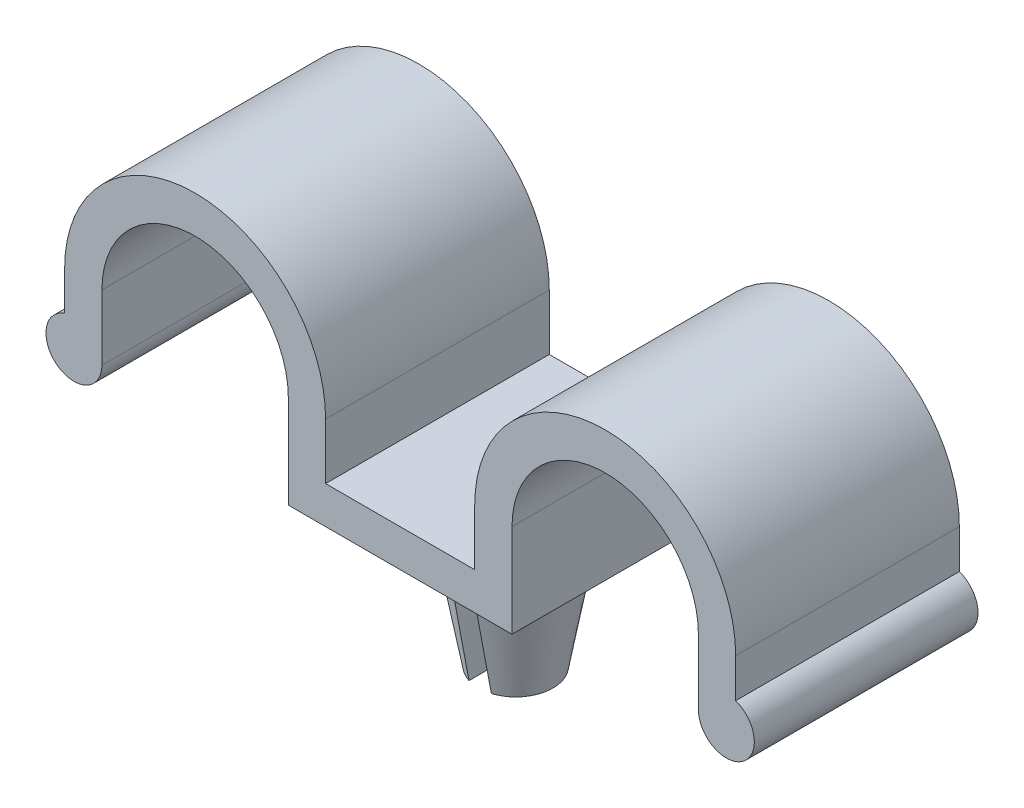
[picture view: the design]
ISO-10303-21;
HEADER;
FILE_DESCRIPTION(('STEP AP214'),'2;1');
FILE_NAME('part.step','',(''),(''),'','','');
FILE_SCHEMA(('AUTOMOTIVE_DESIGN { 1 0 10303 214 1 1 1 1 }'));
ENDSEC;
DATA;
#1=APPLICATION_CONTEXT('core data for automotive mechanical design processes');
#2=APPLICATION_PROTOCOL_DEFINITION('international standard','automotive_design',2000,#1);
#3=PRODUCT_CONTEXT('',#1,'mechanical');
#4=PRODUCT('Part','Part','',(#3));
#5=PRODUCT_RELATED_PRODUCT_CATEGORY('part','',(#4));
#6=PRODUCT_DEFINITION_FORMATION('','',#4);
#7=PRODUCT_DEFINITION_CONTEXT('part definition',#1,'design');
#8=PRODUCT_DEFINITION('design','',#6,#7);
#9=PRODUCT_DEFINITION_SHAPE('','',#8);
#10=(LENGTH_UNIT() NAMED_UNIT(*) SI_UNIT(.MILLI.,.METRE.));
#11=(NAMED_UNIT(*) PLANE_ANGLE_UNIT() SI_UNIT($,.RADIAN.));
#12=(NAMED_UNIT(*) SI_UNIT($,.STERADIAN.) SOLID_ANGLE_UNIT());
#13=UNCERTAINTY_MEASURE_WITH_UNIT(LENGTH_MEASURE(1.E-05),#10,'distance_accuracy_value','');
#14=(GEOMETRIC_REPRESENTATION_CONTEXT(3) GLOBAL_UNCERTAINTY_ASSIGNED_CONTEXT((#13)) GLOBAL_UNIT_ASSIGNED_CONTEXT((#10,
#11,#12)) REPRESENTATION_CONTEXT('',''));
#15=CARTESIAN_POINT('',(0.,0.,0.));
#16=DIRECTION('',(0.,0.,1.));
#17=DIRECTION('',(1.,0.,0.));
#18=AXIS2_PLACEMENT_3D('',#15,#16,#17);
#19=CARTESIAN_POINT('',(-6.858,-7.874,0.));
#20=DIRECTION('',(0.,-1.,0.));
#21=DIRECTION('',(0.,0.,-1.));
#22=AXIS2_PLACEMENT_3D('',#19,#20,#21);
#23=PLANE('',#22);
#24=DIRECTION('',(0.,0.,1.));
#25=VECTOR('',#24,1.);
#26=CARTESIAN_POINT('',(-7.239,-7.874,-3.81));
#27=LINE('',#26,#25);
#28=CARTESIAN_POINT('',(-7.239,-7.874,-1.21150278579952));
#29=VERTEX_POINT('',#28);
#30=CARTESIAN_POINT('',(-7.239,-7.874,1.21150278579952));
#31=VERTEX_POINT('',#30);
#32=EDGE_CURVE('E524',#29,#31,#27,.T.);
#33=ORIENTED_EDGE('',*,*,#32,.T.);
#34=CARTESIAN_POINT('',(-6.858,-7.874,0.));
#35=DIRECTION('',(0.,-1.,0.));
#36=DIRECTION('',(0.,0.,-1.));
#37=AXIS2_PLACEMENT_3D('',#34,#35,#36);
#38=CIRCLE('',#37,1.27);
#39=EDGE_CURVE('E413',#31,#29,#38,.T.);
#40=ORIENTED_EDGE('',*,*,#39,.T.);
#41=EDGE_LOOP('',(#33,#40));
#42=FACE_BOUND('',#41,.T.);
#43=ADVANCED_FACE('F34',(#42),#23,.T.);
#44=CARTESIAN_POINT('',(-6.858,-7.874,0.));
#45=DIRECTION('',(0.,1.,0.));
#46=DIRECTION('',(0.,0.,1.));
#47=AXIS2_PLACEMENT_3D('',#44,#45,#46);
#48=CONICAL_SURFACE('',#47,1.27,0.179853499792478);
#49=CARTESIAN_POINT('',(-7.239,-9.73878944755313,-0.849412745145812));
#50=CARTESIAN_POINT('',(-7.239,-9.48062278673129,-0.900807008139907));
#51=CARTESIAN_POINT('',(-7.239,-9.22232851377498,-0.951552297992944));
#52=CARTESIAN_POINT('',(-7.239,-8.7055574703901,-1.05209980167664));
#53=CARTESIAN_POINT('',(-7.239,-8.4470807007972,-1.10190201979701));
#54=CARTESIAN_POINT('',(-7.239,-7.96393825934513,-1.1944225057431));
#55=CARTESIAN_POINT('',(-7.239,-7.73928633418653,-1.2372128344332));
#56=CARTESIAN_POINT('',(-7.239,-7.14364629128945,-1.35021271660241));
#57=CARTESIAN_POINT('',(-7.239,-6.77260404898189,-1.42013701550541));
#58=CARTESIAN_POINT('',(-7.239,-6.03041303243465,-1.55941958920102));
#59=CARTESIAN_POINT('',(-7.239,-5.65926425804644,-1.62877786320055));
#60=CARTESIAN_POINT('',(-7.239,-4.58924213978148,-1.82817101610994));
#61=CARTESIAN_POINT('',(-7.239,-3.89027873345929,-1.95772240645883));
#62=CARTESIAN_POINT('',(-7.239,-2.49221927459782,-2.21610859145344));
#63=CARTESIAN_POINT('',(-7.23900000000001,-1.79312322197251,-2.34494338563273));
#64=CARTESIAN_POINT('',(-7.23900000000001,-0.394858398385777,-2.60217341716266));
#65=CARTESIAN_POINT('',(-7.23900000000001,0.304310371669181,-2.73056865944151));
#66=CARTESIAN_POINT('',(-7.23900000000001,1.7027014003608,-2.98706215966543));
#67=CARTESIAN_POINT('',(-7.23900000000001,2.40192365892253,-3.11516041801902));
#68=CARTESIAN_POINT('',(-7.23900000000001,3.10116007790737,-3.24318091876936));
#69=B_SPLINE_CURVE_WITH_KNOTS('',3,(#49,#50,#51,#52,#53,#54,#55,#56,#57,#58,#59,#60,#61,#62,#63,
#64,#65,#66,#67,#68),.UNSPECIFIED.,.F.,.F.,(4,2,2,2,2,2,2,2,2,4),(0.,0.789694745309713,
1.57938589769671,2.26545823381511,3.39817786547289,4.53089908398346,6.66350237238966,
8.7961070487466,10.9286877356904,13.0612654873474),.UNSPECIFIED.);
#70=CARTESIAN_POINT('',(-7.239,-5.08,-1.73669888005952));
#71=VERTEX_POINT('',#70);
#72=EDGE_CURVE('E396',#29,#71,#69,.T.);
#73=ORIENTED_EDGE('',*,*,#72,.F.);
#74=ORIENTED_EDGE('',*,*,#39,.F.);
#75=CARTESIAN_POINT('',(-7.239,-9.73878944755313,0.849412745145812));
#76=CARTESIAN_POINT('',(-7.239,-9.48062278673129,0.900807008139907));
#77=CARTESIAN_POINT('',(-7.239,-9.22232851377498,0.951552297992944));
#78=CARTESIAN_POINT('',(-7.239,-8.7055574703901,1.05209980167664));
#79=CARTESIAN_POINT('',(-7.239,-8.4470807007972,1.10190201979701));
#80=CARTESIAN_POINT('',(-7.239,-7.96393825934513,1.1944225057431));
#81=CARTESIAN_POINT('',(-7.239,-7.73928633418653,1.2372128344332));
#82=CARTESIAN_POINT('',(-7.239,-7.14364629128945,1.35021271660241));
#83=CARTESIAN_POINT('',(-7.239,-6.77260404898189,1.42013701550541));
#84=CARTESIAN_POINT('',(-7.239,-6.03041303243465,1.55941958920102));
#85=CARTESIAN_POINT('',(-7.239,-5.65926425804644,1.62877786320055));
#86=CARTESIAN_POINT('',(-7.239,-4.58924213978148,1.82817101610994));
#87=CARTESIAN_POINT('',(-7.239,-3.89027873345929,1.95772240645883));
#88=CARTESIAN_POINT('',(-7.239,-2.49221927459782,2.21610859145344));
#89=CARTESIAN_POINT('',(-7.23900000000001,-1.79312322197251,2.34494338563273));
#90=CARTESIAN_POINT('',(-7.23900000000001,-0.394858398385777,2.60217341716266));
#91=CARTESIAN_POINT('',(-7.23900000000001,0.304310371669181,2.73056865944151));
#92=CARTESIAN_POINT('',(-7.23900000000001,1.7027014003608,2.98706215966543));
#93=CARTESIAN_POINT('',(-7.23900000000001,2.40192365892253,3.11516041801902));
#94=CARTESIAN_POINT('',(-7.23900000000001,3.10116007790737,3.24318091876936));
#95=B_SPLINE_CURVE_WITH_KNOTS('',3,(#75,#76,#77,#78,#79,#80,#81,#82,#83,#84,#85,#86,#87,#88,#89,
#90,#91,#92,#93,#94),.UNSPECIFIED.,.F.,.F.,(4,2,2,2,2,2,2,2,2,4),(0.,0.789694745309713,
1.57938589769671,2.26545823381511,3.39817786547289,4.53089908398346,6.66350237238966,
8.7961070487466,10.9286877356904,13.0612654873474),.UNSPECIFIED.);
#96=CARTESIAN_POINT('',(-7.239,-5.08,1.73669888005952));
#97=VERTEX_POINT('',#96);
#98=EDGE_CURVE('E383',#97,#31,#95,.F.);
#99=ORIENTED_EDGE('',*,*,#98,.F.);
#100=CARTESIAN_POINT('',(-6.858,-5.08,0.));
#101=DIRECTION('',(0.,-1.,0.));
#102=DIRECTION('',(0.,0.,-1.));
#103=AXIS2_PLACEMENT_3D('',#100,#101,#102);
#104=CIRCLE('',#103,1.778);
#105=EDGE_CURVE('E409',#97,#71,#104,.T.);
#106=ORIENTED_EDGE('',*,*,#105,.T.);
#107=EDGE_LOOP('',(#73,#74,#99,#106));
#108=FACE_BOUND('',#107,.T.);
#109=ADVANCED_FACE('F371',(#108),#48,.T.);
#110=CARTESIAN_POINT('',(-6.858,-3.175,0.));
#111=DIRECTION('',(0.,-1.,0.));
#112=DIRECTION('',(0.,0.,-1.));
#113=AXIS2_PLACEMENT_3D('',#110,#111,#112);
#114=CYLINDRICAL_SURFACE('',#113,1.778);
#115=DIRECTION('',(0.,-1.,0.));
#116=VECTOR('',#115,1.);
#117=CARTESIAN_POINT('',(-7.239,-3.175,-1.73669888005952));
#118=LINE('',#117,#116);
#119=CARTESIAN_POINT('',(-7.239,-4.826,-1.73669888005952));
#120=VERTEX_POINT('',#119);
#121=EDGE_CURVE('E392',#71,#120,#118,.F.);
#122=ORIENTED_EDGE('',*,*,#121,.F.);
#123=ORIENTED_EDGE('',*,*,#105,.F.);
#124=DIRECTION('',(0.,-1.,0.));
#125=VECTOR('',#124,1.);
#126=CARTESIAN_POINT('',(-7.239,-3.175,1.73669888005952));
#127=LINE('',#126,#125);
#128=CARTESIAN_POINT('',(-7.239,-4.826,1.73669888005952));
#129=VERTEX_POINT('',#128);
#130=EDGE_CURVE('E391',#129,#97,#127,.T.);
#131=ORIENTED_EDGE('',*,*,#130,.F.);
#132=CARTESIAN_POINT('',(-6.858,-4.826,0.));
#133=DIRECTION('',(0.,-1.,0.));
#134=DIRECTION('',(0.,0.,-1.));
#135=AXIS2_PLACEMENT_3D('',#132,#133,#134);
#136=CIRCLE('',#135,1.778);
#137=EDGE_CURVE('E407',#129,#120,#136,.T.);
#138=ORIENTED_EDGE('',*,*,#137,.T.);
#139=EDGE_LOOP('',(#122,#123,#131,#138));
#140=FACE_BOUND('',#139,.T.);
#141=ADVANCED_FACE('F511',(#140),#114,.T.);
#142=CARTESIAN_POINT('',(-5.08,-4.826,0.));
#143=DIRECTION('',(0.,1.,0.));
#144=DIRECTION('',(0.,0.,1.));
#145=AXIS2_PLACEMENT_3D('',#142,#143,#144);
#146=PLANE('',#145);
#147=DIRECTION('',(0.,0.,1.));
#148=VECTOR('',#147,1.);
#149=CARTESIAN_POINT('',(-7.239,-4.826,0.));
#150=LINE('',#149,#148);
#151=CARTESIAN_POINT('',(-7.239,-4.826,-1.47560665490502));
#152=VERTEX_POINT('',#151);
#153=EDGE_CURVE('E310',#120,#152,#150,.T.);
#154=ORIENTED_EDGE('',*,*,#153,.F.);
#155=ORIENTED_EDGE('',*,*,#137,.F.);
#156=CARTESIAN_POINT('',(-7.239,-4.826,1.47560665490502));
#157=VERTEX_POINT('',#156);
#158=EDGE_CURVE('E530',#157,#129,#150,.T.);
#159=ORIENTED_EDGE('',*,*,#158,.F.);
#160=CARTESIAN_POINT('',(-6.858,-4.826,0.));
#161=DIRECTION('',(0.,-1.,0.));
#162=DIRECTION('',(0.,0.,-1.));
#163=AXIS2_PLACEMENT_3D('',#160,#161,#162);
#164=CIRCLE('',#163,1.524);
#165=EDGE_CURVE('E405',#157,#152,#164,.T.);
#166=ORIENTED_EDGE('',*,*,#165,.T.);
#167=EDGE_LOOP('',(#154,#155,#159,#166));
#168=FACE_BOUND('',#167,.T.);
#169=ADVANCED_FACE('F546',(#168),#146,.T.);
#170=CARTESIAN_POINT('',(-3.175,-3.175,3.81));
#171=DIRECTION('',(0.,1.,0.));
#172=DIRECTION('',(-1.,0.,0.));
#173=AXIS2_PLACEMENT_3D('',#170,#171,#172);
#174=PLANE('',#173);
#175=CARTESIAN_POINT('',(-6.858,-3.175,0.));
#176=DIRECTION('',(0.,-1.,0.));
#177=DIRECTION('',(0.,0.,-1.));
#178=AXIS2_PLACEMENT_3D('',#175,#176,#177);
#179=CIRCLE('',#178,1.524);
#180=CARTESIAN_POINT('',(-6.858,-3.175,-1.524));
#181=VERTEX_POINT('',#180);
#182=EDGE_CURVE('E402',#181,#181,#179,.T.);
#183=ORIENTED_EDGE('',*,*,#182,.F.);
#184=EDGE_LOOP('',(#183));
#185=FACE_BOUND('',#184,.T.);
#186=DIRECTION('',(1.,0.,0.));
#187=VECTOR('',#186,1.);
#188=CARTESIAN_POINT('',(-3.175,-3.175,-3.81));
#189=LINE('',#188,#187);
#190=CARTESIAN_POINT('',(-10.795,-3.175,-3.81));
#191=VERTEX_POINT('',#190);
#192=CARTESIAN_POINT('',(-3.175,-3.175,-3.81));
#193=VERTEX_POINT('',#192);
#194=EDGE_CURVE('E191',#191,#193,#189,.T.);
#195=ORIENTED_EDGE('',*,*,#194,.T.);
#196=DIRECTION('',(0.,0.,-1.));
#197=VECTOR('',#196,1.);
#198=CARTESIAN_POINT('',(-3.175,-3.175,3.81));
#199=LINE('',#198,#197);
#200=CARTESIAN_POINT('',(-3.175,-3.175,3.81));
#201=VERTEX_POINT('',#200);
#202=EDGE_CURVE('E260',#201,#193,#199,.T.);
#203=ORIENTED_EDGE('',*,*,#202,.F.);
#204=DIRECTION('',(1.,0.,0.));
#205=VECTOR('',#204,1.);
#206=CARTESIAN_POINT('',(-3.175,-3.175,3.81));
#207=LINE('',#206,#205);
#208=CARTESIAN_POINT('',(-10.795,-3.175,3.81));
#209=VERTEX_POINT('',#208);
#210=EDGE_CURVE('E223',#209,#201,#207,.T.);
#211=ORIENTED_EDGE('',*,*,#210,.F.);
#212=DIRECTION('',(0.,0.,-1.));
#213=VECTOR('',#212,1.);
#214=CARTESIAN_POINT('',(-10.795,-3.175,3.81));
#215=LINE('',#214,#213);
#216=EDGE_CURVE('E187',#209,#191,#215,.T.);
#217=ORIENTED_EDGE('',*,*,#216,.T.);
#218=EDGE_LOOP('',(#195,#203,#211,#217));
#219=FACE_BOUND('',#218,.T.);
#220=ADVANCED_FACE('F36',(#185,#219),#174,.F.);
#221=CARTESIAN_POINT('',(-3.175,0.,3.81));
#222=DIRECTION('',(-1.,0.,0.));
#223=DIRECTION('',(0.,0.,1.));
#224=AXIS2_PLACEMENT_3D('',#221,#222,#223);
#225=PLANE('',#224);
#226=DIRECTION('',(0.,1.,0.));
#227=VECTOR('',#226,1.);
#228=CARTESIAN_POINT('',(-3.175,0.,-3.81));
#229=LINE('',#228,#227);
#230=CARTESIAN_POINT('',(-3.175,0.,-3.81));
#231=VERTEX_POINT('',#230);
#232=EDGE_CURVE('E194',#193,#231,#229,.T.);
#233=ORIENTED_EDGE('',*,*,#232,.T.);
#234=DIRECTION('',(0.,0.,-1.));
#235=VECTOR('',#234,1.);
#236=CARTESIAN_POINT('',(-3.175,0.,3.81));
#237=LINE('',#236,#235);
#238=CARTESIAN_POINT('',(-3.175,0.,3.81));
#239=VERTEX_POINT('',#238);
#240=EDGE_CURVE('E257',#239,#231,#237,.T.);
#241=ORIENTED_EDGE('',*,*,#240,.F.);
#242=DIRECTION('',(0.,1.,0.));
#243=VECTOR('',#242,1.);
#244=CARTESIAN_POINT('',(-3.175,0.,3.81));
#245=LINE('',#244,#243);
#246=EDGE_CURVE('E124',#201,#239,#245,.T.);
#247=ORIENTED_EDGE('',*,*,#246,.F.);
#248=ORIENTED_EDGE('',*,*,#202,.T.);
#249=EDGE_LOOP('',(#233,#241,#247,#248));
#250=FACE_BOUND('',#249,.T.);
#251=ADVANCED_FACE('F456',(#250),#225,.F.);
#252=CARTESIAN_POINT('',(0.,0.,3.81));
#253=DIRECTION('',(0.,0.,-1.));
#254=DIRECTION('',(-1.,0.,0.));
#255=AXIS2_PLACEMENT_3D('',#252,#253,#254);
#256=CYLINDRICAL_SURFACE('',#255,3.175);
#257=CARTESIAN_POINT('',(0.,0.,-3.81));
#258=DIRECTION('',(0.,0.,-1.));
#259=DIRECTION('',(1.,0.,0.));
#260=AXIS2_PLACEMENT_3D('',#257,#258,#259);
#261=CIRCLE('',#260,3.175);
#262=CARTESIAN_POINT('',(3.175,0.,-3.81));
#263=VERTEX_POINT('',#262);
#264=EDGE_CURVE('E197',#231,#263,#261,.T.);
#265=ORIENTED_EDGE('',*,*,#264,.T.);
#266=DIRECTION('',(0.,0.,-1.));
#267=VECTOR('',#266,1.);
#268=CARTESIAN_POINT('',(3.175,0.,3.81));
#269=LINE('',#268,#267);
#270=CARTESIAN_POINT('',(3.175,0.,3.81));
#271=VERTEX_POINT('',#270);
#272=EDGE_CURVE('E254',#271,#263,#269,.T.);
#273=ORIENTED_EDGE('',*,*,#272,.F.);
#274=CARTESIAN_POINT('',(0.,0.,3.81));
#275=DIRECTION('',(0.,0.,-1.));
#276=DIRECTION('',(1.,0.,0.));
#277=AXIS2_PLACEMENT_3D('',#274,#275,#276);
#278=CIRCLE('',#277,3.175);
#279=EDGE_CURVE('E418',#239,#271,#278,.T.);
#280=ORIENTED_EDGE('',*,*,#279,.F.);
#281=ORIENTED_EDGE('',*,*,#240,.T.);
#282=EDGE_LOOP('',(#265,#273,#280,#281));
#283=FACE_BOUND('',#282,.T.);
#284=ADVANCED_FACE('F459',(#283),#256,.F.);
#285=CARTESIAN_POINT('',(3.175,0.,3.81));
#286=DIRECTION('',(1.,0.,0.));
#287=DIRECTION('',(0.,1.,0.));
#288=AXIS2_PLACEMENT_3D('',#285,#286,#287);
#289=PLANE('',#288);
#290=DIRECTION('',(0.,-1.,0.));
#291=VECTOR('',#290,1.);
#292=CARTESIAN_POINT('',(3.175,0.,-3.81));
#293=LINE('',#292,#291);
#294=CARTESIAN_POINT('',(3.175,-2.2225,-3.81));
#295=VERTEX_POINT('',#294);
#296=EDGE_CURVE('E199',#263,#295,#293,.T.);
#297=ORIENTED_EDGE('',*,*,#296,.T.);
#298=DIRECTION('',(0.,0.,-1.));
#299=VECTOR('',#298,1.);
#300=CARTESIAN_POINT('',(3.175,-2.2225,3.81));
#301=LINE('',#300,#299);
#302=CARTESIAN_POINT('',(3.175,-2.2225,3.81));
#303=VERTEX_POINT('',#302);
#304=EDGE_CURVE('E251',#303,#295,#301,.T.);
#305=ORIENTED_EDGE('',*,*,#304,.F.);
#306=DIRECTION('',(0.,-1.,0.));
#307=VECTOR('',#306,1.);
#308=CARTESIAN_POINT('',(3.175,0.,3.81));
#309=LINE('',#308,#307);
#310=EDGE_CURVE('E420',#271,#303,#309,.T.);
#311=ORIENTED_EDGE('',*,*,#310,.F.);
#312=ORIENTED_EDGE('',*,*,#272,.T.);
#313=EDGE_LOOP('',(#297,#305,#311,#312));
#314=FACE_BOUND('',#313,.T.);
#315=ADVANCED_FACE('F464',(#314),#289,.F.);
#316=CARTESIAN_POINT('',(4.1275,-2.2225,3.81));
#317=DIRECTION('',(0.,0.,-1.));
#318=DIRECTION('',(-1.,0.,0.));
#319=AXIS2_PLACEMENT_3D('',#316,#317,#318);
#320=CYLINDRICAL_SURFACE('',#319,0.9525);
#321=CARTESIAN_POINT('',(4.1275,-2.2225,-3.81));
#322=DIRECTION('',(0.,0.,1.));
#323=DIRECTION('',(1.,0.,0.));
#324=AXIS2_PLACEMENT_3D('',#321,#322,#323);
#325=CIRCLE('',#324,0.9525);
#326=CARTESIAN_POINT('',(4.445,-1.32447438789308,-3.81));
#327=VERTEX_POINT('',#326);
#328=EDGE_CURVE('E201',#295,#327,#325,.T.);
#329=ORIENTED_EDGE('',*,*,#328,.T.);
#330=DIRECTION('',(0.,0.,-1.));
#331=VECTOR('',#330,1.);
#332=CARTESIAN_POINT('',(4.445,-1.32447438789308,3.81));
#333=LINE('',#332,#331);
#334=CARTESIAN_POINT('',(4.445,-1.32447438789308,3.81));
#335=VERTEX_POINT('',#334);
#336=EDGE_CURVE('E248',#335,#327,#333,.T.);
#337=ORIENTED_EDGE('',*,*,#336,.F.);
#338=CARTESIAN_POINT('',(4.1275,-2.2225,3.81));
#339=DIRECTION('',(0.,0.,1.));
#340=DIRECTION('',(1.,0.,0.));
#341=AXIS2_PLACEMENT_3D('',#338,#339,#340);
#342=CIRCLE('',#341,0.9525);
#343=EDGE_CURVE('E422',#303,#335,#342,.T.);
#344=ORIENTED_EDGE('',*,*,#343,.F.);
#345=ORIENTED_EDGE('',*,*,#304,.T.);
#346=EDGE_LOOP('',(#329,#337,#344,#345));
#347=FACE_BOUND('',#346,.T.);
#348=ADVANCED_FACE('F470',(#347),#320,.T.);
#349=CARTESIAN_POINT('',(4.445,0.,3.81));
#350=DIRECTION('',(-1.,0.,0.));
#351=DIRECTION('',(0.,0.,1.));
#352=AXIS2_PLACEMENT_3D('',#349,#350,#351);
#353=PLANE('',#352);
#354=DIRECTION('',(0.,1.,0.));
#355=VECTOR('',#354,1.);
#356=CARTESIAN_POINT('',(4.445,0.,-3.81));
#357=LINE('',#356,#355);
#358=CARTESIAN_POINT('',(4.445,0.,-3.81));
#359=VERTEX_POINT('',#358);
#360=EDGE_CURVE('E203',#327,#359,#357,.T.);
#361=ORIENTED_EDGE('',*,*,#360,.T.);
#362=DIRECTION('',(0.,0.,-1.));
#363=VECTOR('',#362,1.);
#364=CARTESIAN_POINT('',(4.445,0.,3.81));
#365=LINE('',#364,#363);
#366=CARTESIAN_POINT('',(4.445,0.,3.81));
#367=VERTEX_POINT('',#366);
#368=EDGE_CURVE('E245',#367,#359,#365,.T.);
#369=ORIENTED_EDGE('',*,*,#368,.F.);
#370=DIRECTION('',(0.,1.,0.));
#371=VECTOR('',#370,1.);
#372=CARTESIAN_POINT('',(4.445,0.,3.81));
#373=LINE('',#372,#371);
#374=EDGE_CURVE('E424',#335,#367,#373,.T.);
#375=ORIENTED_EDGE('',*,*,#374,.F.);
#376=ORIENTED_EDGE('',*,*,#336,.T.);
#377=EDGE_LOOP('',(#361,#369,#375,#376));
#378=FACE_BOUND('',#377,.T.);
#379=ADVANCED_FACE('F474',(#378),#353,.F.);
#380=CARTESIAN_POINT('',(0.,0.,3.81));
#381=DIRECTION('',(0.,0.,-1.));
#382=DIRECTION('',(-1.,0.,0.));
#383=AXIS2_PLACEMENT_3D('',#380,#381,#382);
#384=CYLINDRICAL_SURFACE('',#383,4.445);
#385=CARTESIAN_POINT('',(0.,0.,-3.81));
#386=DIRECTION('',(0.,0.,1.));
#387=DIRECTION('',(1.,0.,0.));
#388=AXIS2_PLACEMENT_3D('',#385,#386,#387);
#389=CIRCLE('',#388,4.445);
#390=CARTESIAN_POINT('',(-4.445,0.,-3.81));
#391=VERTEX_POINT('',#390);
#392=EDGE_CURVE('E205',#359,#391,#389,.T.);
#393=ORIENTED_EDGE('',*,*,#392,.T.);
#394=DIRECTION('',(0.,0.,-1.));
#395=VECTOR('',#394,1.);
#396=CARTESIAN_POINT('',(-4.445,0.,3.81));
#397=LINE('',#396,#395);
#398=CARTESIAN_POINT('',(-4.445,0.,3.81));
#399=VERTEX_POINT('',#398);
#400=EDGE_CURVE('E242',#399,#391,#397,.T.);
#401=ORIENTED_EDGE('',*,*,#400,.F.);
#402=CARTESIAN_POINT('',(0.,0.,3.81));
#403=DIRECTION('',(0.,0.,1.));
#404=DIRECTION('',(1.,0.,0.));
#405=AXIS2_PLACEMENT_3D('',#402,#403,#404);
#406=CIRCLE('',#405,4.445);
#407=EDGE_CURVE('E426',#367,#399,#406,.T.);
#408=ORIENTED_EDGE('',*,*,#407,.F.);
#409=ORIENTED_EDGE('',*,*,#368,.T.);
#410=EDGE_LOOP('',(#393,#401,#408,#409));
#411=FACE_BOUND('',#410,.T.);
#412=ADVANCED_FACE('F479',(#411),#384,.T.);
#413=CARTESIAN_POINT('',(-4.445,0.,3.81));
#414=DIRECTION('',(1.,0.,0.));
#415=DIRECTION('',(0.,0.,-1.));
#416=AXIS2_PLACEMENT_3D('',#413,#414,#415);
#417=PLANE('',#416);
#418=DIRECTION('',(0.,-1.,0.));
#419=VECTOR('',#418,1.);
#420=CARTESIAN_POINT('',(-4.445,0.,-3.81));
#421=LINE('',#420,#419);
#422=CARTESIAN_POINT('',(-4.445,-1.905,-3.81));
#423=VERTEX_POINT('',#422);
#424=EDGE_CURVE('E207',#391,#423,#421,.T.);
#425=ORIENTED_EDGE('',*,*,#424,.T.);
#426=DIRECTION('',(0.,0.,-1.));
#427=VECTOR('',#426,1.);
#428=CARTESIAN_POINT('',(-4.445,-1.905,3.81));
#429=LINE('',#428,#427);
#430=CARTESIAN_POINT('',(-4.445,-1.905,3.81));
#431=VERTEX_POINT('',#430);
#432=EDGE_CURVE('E239',#431,#423,#429,.T.);
#433=ORIENTED_EDGE('',*,*,#432,.F.);
#434=DIRECTION('',(0.,-1.,0.));
#435=VECTOR('',#434,1.);
#436=CARTESIAN_POINT('',(-4.445,0.,3.81));
#437=LINE('',#436,#435);
#438=EDGE_CURVE('E428',#399,#431,#437,.T.);
#439=ORIENTED_EDGE('',*,*,#438,.F.);
#440=ORIENTED_EDGE('',*,*,#400,.T.);
#441=EDGE_LOOP('',(#425,#433,#439,#440));
#442=FACE_BOUND('',#441,.T.);
#443=ADVANCED_FACE('F485',(#442),#417,.F.);
#444=CARTESIAN_POINT('',(-9.525,-1.905,3.81));
#445=DIRECTION('',(0.,-1.,0.));
#446=DIRECTION('',(1.,0.,0.));
#447=AXIS2_PLACEMENT_3D('',#444,#445,#446);
#448=PLANE('',#447);
#449=DIRECTION('',(-1.,0.,0.));
#450=VECTOR('',#449,1.);
#451=CARTESIAN_POINT('',(-9.525,-1.905,-3.81));
#452=LINE('',#451,#450);
#453=CARTESIAN_POINT('',(-9.525,-1.905,-3.81));
#454=VERTEX_POINT('',#453);
#455=EDGE_CURVE('E209',#423,#454,#452,.T.);
#456=ORIENTED_EDGE('',*,*,#455,.T.);
#457=DIRECTION('',(0.,0.,-1.));
#458=VECTOR('',#457,1.);
#459=CARTESIAN_POINT('',(-9.525,-1.905,3.81));
#460=LINE('',#459,#458);
#461=CARTESIAN_POINT('',(-9.525,-1.905,3.81));
#462=VERTEX_POINT('',#461);
#463=EDGE_CURVE('E236',#462,#454,#460,.T.);
#464=ORIENTED_EDGE('',*,*,#463,.F.);
#465=DIRECTION('',(-1.,0.,0.));
#466=VECTOR('',#465,1.);
#467=CARTESIAN_POINT('',(-9.525,-1.905,3.81));
#468=LINE('',#467,#466);
#469=EDGE_CURVE('E430',#431,#462,#468,.T.);
#470=ORIENTED_EDGE('',*,*,#469,.F.);
#471=ORIENTED_EDGE('',*,*,#432,.T.);
#472=EDGE_LOOP('',(#456,#464,#470,#471));
#473=FACE_BOUND('',#472,.T.);
#474=ADVANCED_FACE('F489',(#473),#448,.F.);
#475=CARTESIAN_POINT('',(-9.525,0.,3.81));
#476=DIRECTION('',(-1.,0.,0.));
#477=DIRECTION('',(0.,0.,1.));
#478=AXIS2_PLACEMENT_3D('',#475,#476,#477);
#479=PLANE('',#478);
#480=DIRECTION('',(0.,1.,0.));
#481=VECTOR('',#480,1.);
#482=CARTESIAN_POINT('',(-9.525,0.,-3.81));
#483=LINE('',#482,#481);
#484=CARTESIAN_POINT('',(-9.525,0.,-3.81));
#485=VERTEX_POINT('',#484);
#486=EDGE_CURVE('E211',#454,#485,#483,.T.);
#487=ORIENTED_EDGE('',*,*,#486,.T.);
#488=DIRECTION('',(0.,0.,-1.));
#489=VECTOR('',#488,1.);
#490=CARTESIAN_POINT('',(-9.525,0.,3.81));
#491=LINE('',#490,#489);
#492=CARTESIAN_POINT('',(-9.525,0.,3.81));
#493=VERTEX_POINT('',#492);
#494=EDGE_CURVE('E233',#493,#485,#491,.T.);
#495=ORIENTED_EDGE('',*,*,#494,.F.);
#496=DIRECTION('',(0.,1.,0.));
#497=VECTOR('',#496,1.);
#498=CARTESIAN_POINT('',(-9.525,0.,3.81));
#499=LINE('',#498,#497);
#500=EDGE_CURVE('E432',#462,#493,#499,.T.);
#501=ORIENTED_EDGE('',*,*,#500,.F.);
#502=ORIENTED_EDGE('',*,*,#463,.T.);
#503=EDGE_LOOP('',(#487,#495,#501,#502));
#504=FACE_BOUND('',#503,.T.);
#505=ADVANCED_FACE('F494',(#504),#479,.F.);
#506=CARTESIAN_POINT('',(-13.97,0.,3.81));
#507=DIRECTION('',(0.,0.,-1.));
#508=DIRECTION('',(-1.,0.,0.));
#509=AXIS2_PLACEMENT_3D('',#506,#507,#508);
#510=CYLINDRICAL_SURFACE('',#509,4.445);
#511=CARTESIAN_POINT('',(-13.97,0.,-3.81));
#512=DIRECTION('',(0.,0.,1.));
#513=DIRECTION('',(-1.,0.,0.));
#514=AXIS2_PLACEMENT_3D('',#511,#512,#513);
#515=CIRCLE('',#514,4.445);
#516=CARTESIAN_POINT('',(-18.415,0.,-3.81));
#517=VERTEX_POINT('',#516);
#518=EDGE_CURVE('E213',#485,#517,#515,.T.);
#519=ORIENTED_EDGE('',*,*,#518,.T.);
#520=DIRECTION('',(0.,0.,-1.));
#521=VECTOR('',#520,1.);
#522=CARTESIAN_POINT('',(-18.415,0.,3.81));
#523=LINE('',#522,#521);
#524=CARTESIAN_POINT('',(-18.415,0.,3.81));
#525=VERTEX_POINT('',#524);
#526=EDGE_CURVE('E230',#525,#517,#523,.T.);
#527=ORIENTED_EDGE('',*,*,#526,.F.);
#528=CARTESIAN_POINT('',(-13.97,0.,3.81));
#529=DIRECTION('',(0.,0.,1.));
#530=DIRECTION('',(-1.,0.,0.));
#531=AXIS2_PLACEMENT_3D('',#528,#529,#530);
#532=CIRCLE('',#531,4.445);
#533=EDGE_CURVE('E434',#493,#525,#532,.T.);
#534=ORIENTED_EDGE('',*,*,#533,.F.);
#535=ORIENTED_EDGE('',*,*,#494,.T.);
#536=EDGE_LOOP('',(#519,#527,#534,#535));
#537=FACE_BOUND('',#536,.T.);
#538=ADVANCED_FACE('F497',(#537),#510,.T.);
#539=CARTESIAN_POINT('',(-18.415,0.,3.81));
#540=DIRECTION('',(1.,0.,0.));
#541=DIRECTION('',(0.,0.,-1.));
#542=AXIS2_PLACEMENT_3D('',#539,#540,#541);
#543=PLANE('',#542);
#544=DIRECTION('',(0.,-1.,0.));
#545=VECTOR('',#544,1.);
#546=CARTESIAN_POINT('',(-18.415,0.,-3.81));
#547=LINE('',#546,#545);
#548=CARTESIAN_POINT('',(-18.415,-1.32447438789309,-3.81));
#549=VERTEX_POINT('',#548);
#550=EDGE_CURVE('E215',#517,#549,#547,.T.);
#551=ORIENTED_EDGE('',*,*,#550,.T.);
#552=DIRECTION('',(0.,0.,-1.));
#553=VECTOR('',#552,1.);
#554=CARTESIAN_POINT('',(-18.415,-1.32447438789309,3.81));
#555=LINE('',#554,#553);
#556=CARTESIAN_POINT('',(-18.415,-1.32447438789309,3.81));
#557=VERTEX_POINT('',#556);
#558=EDGE_CURVE('E227',#557,#549,#555,.T.);
#559=ORIENTED_EDGE('',*,*,#558,.F.);
#560=DIRECTION('',(0.,-1.,0.));
#561=VECTOR('',#560,1.);
#562=CARTESIAN_POINT('',(-18.415,0.,3.81));
#563=LINE('',#562,#561);
#564=EDGE_CURVE('E436',#525,#557,#563,.T.);
#565=ORIENTED_EDGE('',*,*,#564,.F.);
#566=ORIENTED_EDGE('',*,*,#526,.T.);
#567=EDGE_LOOP('',(#551,#559,#565,#566));
#568=FACE_BOUND('',#567,.T.);
#569=ADVANCED_FACE('F442',(#568),#543,.F.);
#570=CARTESIAN_POINT('',(-18.0975,-2.2225,3.81));
#571=DIRECTION('',(0.,0.,-1.));
#572=DIRECTION('',(-1.,0.,0.));
#573=AXIS2_PLACEMENT_3D('',#570,#571,#572);
#574=CYLINDRICAL_SURFACE('',#573,0.952500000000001);
#575=CARTESIAN_POINT('',(-18.0975,-2.2225,-3.81));
#576=DIRECTION('',(0.,0.,1.));
#577=DIRECTION('',(-1.,0.,0.));
#578=AXIS2_PLACEMENT_3D('',#575,#576,#577);
#579=CIRCLE('',#578,0.952500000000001);
#580=CARTESIAN_POINT('',(-17.145,-2.2225,-3.81));
#581=VERTEX_POINT('',#580);
#582=EDGE_CURVE('E217',#549,#581,#579,.T.);
#583=ORIENTED_EDGE('',*,*,#582,.T.);
#584=DIRECTION('',(0.,0.,-1.));
#585=VECTOR('',#584,1.);
#586=CARTESIAN_POINT('',(-17.145,-2.2225,3.81));
#587=LINE('',#586,#585);
#588=CARTESIAN_POINT('',(-17.145,-2.2225,3.81));
#589=VERTEX_POINT('',#588);
#590=EDGE_CURVE('E182',#589,#581,#587,.T.);
#591=ORIENTED_EDGE('',*,*,#590,.F.);
#592=CARTESIAN_POINT('',(-18.0975,-2.2225,3.81));
#593=DIRECTION('',(0.,0.,1.));
#594=DIRECTION('',(-1.,0.,0.));
#595=AXIS2_PLACEMENT_3D('',#592,#593,#594);
#596=CIRCLE('',#595,0.952500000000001);
#597=EDGE_CURVE('E170',#557,#589,#596,.T.);
#598=ORIENTED_EDGE('',*,*,#597,.F.);
#599=ORIENTED_EDGE('',*,*,#558,.T.);
#600=EDGE_LOOP('',(#583,#591,#598,#599));
#601=FACE_BOUND('',#600,.T.);
#602=ADVANCED_FACE('F446',(#601),#574,.T.);
#603=CARTESIAN_POINT('',(-17.145,0.,3.81));
#604=DIRECTION('',(-1.,0.,0.));
#605=DIRECTION('',(0.,0.,1.));
#606=AXIS2_PLACEMENT_3D('',#603,#604,#605);
#607=PLANE('',#606);
#608=DIRECTION('',(0.,1.,0.));
#609=VECTOR('',#608,1.);
#610=CARTESIAN_POINT('',(-17.145,0.,-3.81));
#611=LINE('',#610,#609);
#612=CARTESIAN_POINT('',(-17.145,0.,-3.81));
#613=VERTEX_POINT('',#612);
#614=EDGE_CURVE('E179',#581,#613,#611,.T.);
#615=ORIENTED_EDGE('',*,*,#614,.T.);
#616=DIRECTION('',(0.,0.,-1.));
#617=VECTOR('',#616,1.);
#618=CARTESIAN_POINT('',(-17.145,0.,3.81));
#619=LINE('',#618,#617);
#620=CARTESIAN_POINT('',(-17.145,0.,3.81));
#621=VERTEX_POINT('',#620);
#622=EDGE_CURVE('E176',#621,#613,#619,.T.);
#623=ORIENTED_EDGE('',*,*,#622,.F.);
#624=DIRECTION('',(0.,1.,0.));
#625=VECTOR('',#624,1.);
#626=CARTESIAN_POINT('',(-17.145,0.,3.81));
#627=LINE('',#626,#625);
#628=EDGE_CURVE('E163',#589,#621,#627,.T.);
#629=ORIENTED_EDGE('',*,*,#628,.F.);
#630=ORIENTED_EDGE('',*,*,#590,.T.);
#631=EDGE_LOOP('',(#615,#623,#629,#630));
#632=FACE_BOUND('',#631,.T.);
#633=ADVANCED_FACE('F177',(#632),#607,.F.);
#634=CARTESIAN_POINT('',(-13.97,0.,3.81));
#635=DIRECTION('',(0.,0.,-1.));
#636=DIRECTION('',(-1.,0.,0.));
#637=AXIS2_PLACEMENT_3D('',#634,#635,#636);
#638=CYLINDRICAL_SURFACE('',#637,3.175);
#639=CARTESIAN_POINT('',(-13.97,0.,-3.81));
#640=DIRECTION('',(0.,0.,-1.));
#641=DIRECTION('',(-1.,0.,0.));
#642=AXIS2_PLACEMENT_3D('',#639,#640,#641);
#643=CIRCLE('',#642,3.175);
#644=CARTESIAN_POINT('',(-10.795,0.,-3.81));
#645=VERTEX_POINT('',#644);
#646=EDGE_CURVE('E220',#613,#645,#643,.T.);
#647=ORIENTED_EDGE('',*,*,#646,.T.);
#648=DIRECTION('',(0.,0.,-1.));
#649=VECTOR('',#648,1.);
#650=CARTESIAN_POINT('',(-10.795,0.,3.81));
#651=LINE('',#650,#649);
#652=CARTESIAN_POINT('',(-10.795,0.,3.81));
#653=VERTEX_POINT('',#652);
#654=EDGE_CURVE('E183',#653,#645,#651,.T.);
#655=ORIENTED_EDGE('',*,*,#654,.F.);
#656=CARTESIAN_POINT('',(-13.97,0.,3.81));
#657=DIRECTION('',(0.,0.,-1.));
#658=DIRECTION('',(-1.,0.,0.));
#659=AXIS2_PLACEMENT_3D('',#656,#657,#658);
#660=CIRCLE('',#659,3.175);
#661=EDGE_CURVE('E167',#621,#653,#660,.T.);
#662=ORIENTED_EDGE('',*,*,#661,.F.);
#663=ORIENTED_EDGE('',*,*,#622,.T.);
#664=EDGE_LOOP('',(#647,#655,#662,#663));
#665=FACE_BOUND('',#664,.T.);
#666=ADVANCED_FACE('F185',(#665),#638,.F.);
#667=CARTESIAN_POINT('',(-10.795,0.,3.81));
#668=DIRECTION('',(1.,0.,0.));
#669=DIRECTION('',(0.,0.,-1.));
#670=AXIS2_PLACEMENT_3D('',#667,#668,#669);
#671=PLANE('',#670);
#672=DIRECTION('',(0.,-1.,0.));
#673=VECTOR('',#672,1.);
#674=CARTESIAN_POINT('',(-10.795,0.,-3.81));
#675=LINE('',#674,#673);
#676=EDGE_CURVE('E115',#645,#191,#675,.T.);
#677=ORIENTED_EDGE('',*,*,#676,.T.);
#678=ORIENTED_EDGE('',*,*,#216,.F.);
#679=DIRECTION('',(0.,-1.,0.));
#680=VECTOR('',#679,1.);
#681=CARTESIAN_POINT('',(-10.795,0.,3.81));
#682=LINE('',#681,#680);
#683=EDGE_CURVE('E58',#653,#209,#682,.T.);
#684=ORIENTED_EDGE('',*,*,#683,.F.);
#685=ORIENTED_EDGE('',*,*,#654,.T.);
#686=EDGE_LOOP('',(#677,#678,#684,#685));
#687=FACE_BOUND('',#686,.T.);
#688=ADVANCED_FACE('F450',(#687),#671,.F.);
#689=CARTESIAN_POINT('',(-13.97,0.,3.81));
#690=DIRECTION('',(0.,0.,-1.));
#691=DIRECTION('',(-1.,0.,0.));
#692=AXIS2_PLACEMENT_3D('',#689,#690,#691);
#693=PLANE('',#692);
#694=ORIENTED_EDGE('',*,*,#210,.T.);
#695=ORIENTED_EDGE('',*,*,#246,.T.);
#696=ORIENTED_EDGE('',*,*,#279,.T.);
#697=ORIENTED_EDGE('',*,*,#310,.T.);
#698=ORIENTED_EDGE('',*,*,#343,.T.);
#699=ORIENTED_EDGE('',*,*,#374,.T.);
#700=ORIENTED_EDGE('',*,*,#407,.T.);
#701=ORIENTED_EDGE('',*,*,#438,.T.);
#702=ORIENTED_EDGE('',*,*,#469,.T.);
#703=ORIENTED_EDGE('',*,*,#500,.T.);
#704=ORIENTED_EDGE('',*,*,#533,.T.);
#705=ORIENTED_EDGE('',*,*,#564,.T.);
#706=ORIENTED_EDGE('',*,*,#597,.T.);
#707=ORIENTED_EDGE('',*,*,#628,.T.);
#708=ORIENTED_EDGE('',*,*,#661,.T.);
#709=ORIENTED_EDGE('',*,*,#683,.T.);
#710=EDGE_LOOP('',(#694,#695,#696,#697,#698,#699,#700,#701,#702,#703,#704,#705,#706,#707,#708,#709));
#711=FACE_BOUND('',#710,.T.);
#712=ADVANCED_FACE('F165',(#711),#693,.F.);
#713=CARTESIAN_POINT('',(-13.97,0.,-3.81));
#714=DIRECTION('',(0.,0.,-1.));
#715=DIRECTION('',(-1.,0.,0.));
#716=AXIS2_PLACEMENT_3D('',#713,#714,#715);
#717=PLANE('',#716);
#718=ORIENTED_EDGE('',*,*,#194,.F.);
#719=ORIENTED_EDGE('',*,*,#676,.F.);
#720=ORIENTED_EDGE('',*,*,#646,.F.);
#721=ORIENTED_EDGE('',*,*,#614,.F.);
#722=ORIENTED_EDGE('',*,*,#582,.F.);
#723=ORIENTED_EDGE('',*,*,#550,.F.);
#724=ORIENTED_EDGE('',*,*,#518,.F.);
#725=ORIENTED_EDGE('',*,*,#486,.F.);
#726=ORIENTED_EDGE('',*,*,#455,.F.);
#727=ORIENTED_EDGE('',*,*,#424,.F.);
#728=ORIENTED_EDGE('',*,*,#392,.F.);
#729=ORIENTED_EDGE('',*,*,#360,.F.);
#730=ORIENTED_EDGE('',*,*,#328,.F.);
#731=ORIENTED_EDGE('',*,*,#296,.F.);
#732=ORIENTED_EDGE('',*,*,#264,.F.);
#733=ORIENTED_EDGE('',*,*,#232,.F.);
#734=EDGE_LOOP('',(#718,#719,#720,#721,#722,#723,#724,#725,#726,#727,#728,#729,#730,#731,#732,#733));
#735=FACE_BOUND('',#734,.T.);
#736=ADVANCED_FACE('F449',(#735),#717,.T.);
#737=DIRECTION('',(0.,0.,1.));
#738=VECTOR('',#737,1.);
#739=CARTESIAN_POINT('',(-6.477,-7.874,-3.81));
#740=LINE('',#739,#738);
#741=CARTESIAN_POINT('',(-6.477,-7.874,-1.21150278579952));
#742=VERTEX_POINT('',#741);
#743=CARTESIAN_POINT('',(-6.477,-7.874,1.21150278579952));
#744=VERTEX_POINT('',#743);
#745=EDGE_CURVE('E520',#742,#744,#740,.T.);
#746=ORIENTED_EDGE('',*,*,#745,.F.);
#747=EDGE_CURVE('E195',#742,#744,#38,.T.);
#748=ORIENTED_EDGE('',*,*,#747,.T.);
#749=EDGE_LOOP('',(#746,#748));
#750=FACE_BOUND('',#749,.T.);
#751=ADVANCED_FACE('F369',(#750),#23,.T.);
#752=CARTESIAN_POINT('',(-6.477,-9.73878944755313,-0.849412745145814));
#753=CARTESIAN_POINT('',(-6.477,-9.48062278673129,-0.900807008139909));
#754=CARTESIAN_POINT('',(-6.477,-9.22232851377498,-0.951552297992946));
#755=CARTESIAN_POINT('',(-6.477,-8.7055574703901,-1.05209980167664));
#756=CARTESIAN_POINT('',(-6.477,-8.4470807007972,-1.10190201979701));
#757=CARTESIAN_POINT('',(-6.477,-7.96393825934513,-1.1944225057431));
#758=CARTESIAN_POINT('',(-6.477,-7.73928633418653,-1.2372128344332));
#759=CARTESIAN_POINT('',(-6.477,-7.14364629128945,-1.35021271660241));
#760=CARTESIAN_POINT('',(-6.477,-6.77260404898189,-1.42013701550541));
#761=CARTESIAN_POINT('',(-6.477,-6.03041303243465,-1.55941958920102));
#762=CARTESIAN_POINT('',(-6.477,-5.65926425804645,-1.62877786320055));
#763=CARTESIAN_POINT('',(-6.477,-4.58924213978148,-1.82817101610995));
#764=CARTESIAN_POINT('',(-6.47700000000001,-3.89027873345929,-1.95772240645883));
#765=CARTESIAN_POINT('',(-6.47700000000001,-2.49221927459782,-2.21610859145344));
#766=CARTESIAN_POINT('',(-6.47700000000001,-1.7931232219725,-2.34494338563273));
#767=CARTESIAN_POINT('',(-6.47700000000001,-0.394858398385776,-2.60217341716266));
#768=CARTESIAN_POINT('',(-6.47700000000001,0.30431037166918,-2.73056865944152));
#769=CARTESIAN_POINT('',(-6.47700000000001,1.7027014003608,-2.98706215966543));
#770=CARTESIAN_POINT('',(-6.47700000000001,2.40192365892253,-3.11516041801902));
#771=CARTESIAN_POINT('',(-6.47700000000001,3.10116007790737,-3.24318091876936));
#772=B_SPLINE_CURVE_WITH_KNOTS('',3,(#752,#753,#754,#755,#756,#757,#758,#759,#760,#761,#762,
#763,#764,#765,#766,#767,#768,#769,#770,#771),.UNSPECIFIED.,.F.,.F.,(4,2,2,2,2,2,2,2,2,4),(0.,
0.789694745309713,1.57938589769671,2.26545823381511,3.39817786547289,4.53089908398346,
6.66350237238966,8.7961070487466,10.9286877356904,13.0612654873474),.UNSPECIFIED.);
#773=CARTESIAN_POINT('',(-6.47700000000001,-5.08,-1.73669888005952));
#774=VERTEX_POINT('',#773);
#775=EDGE_CURVE('E344',#774,#742,#772,.F.);
#776=ORIENTED_EDGE('',*,*,#775,.F.);
#777=CARTESIAN_POINT('',(-6.47700000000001,-5.08,1.73669888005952));
#778=VERTEX_POINT('',#777);
#779=EDGE_CURVE('E410',#774,#778,#104,.T.);
#780=ORIENTED_EDGE('',*,*,#779,.T.);
#781=CARTESIAN_POINT('',(-6.477,-9.73878944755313,0.849412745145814));
#782=CARTESIAN_POINT('',(-6.477,-9.48062278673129,0.900807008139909));
#783=CARTESIAN_POINT('',(-6.477,-9.22232851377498,0.951552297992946));
#784=CARTESIAN_POINT('',(-6.477,-8.7055574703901,1.05209980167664));
#785=CARTESIAN_POINT('',(-6.477,-8.4470807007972,1.10190201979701));
#786=CARTESIAN_POINT('',(-6.477,-7.96393825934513,1.1944225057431));
#787=CARTESIAN_POINT('',(-6.477,-7.73928633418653,1.2372128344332));
#788=CARTESIAN_POINT('',(-6.477,-7.14364629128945,1.35021271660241));
#789=CARTESIAN_POINT('',(-6.477,-6.77260404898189,1.42013701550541));
#790=CARTESIAN_POINT('',(-6.477,-6.03041303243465,1.55941958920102));
#791=CARTESIAN_POINT('',(-6.477,-5.65926425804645,1.62877786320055));
#792=CARTESIAN_POINT('',(-6.477,-4.58924213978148,1.82817101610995));
#793=CARTESIAN_POINT('',(-6.47700000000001,-3.89027873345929,1.95772240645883));
#794=CARTESIAN_POINT('',(-6.47700000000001,-2.49221927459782,2.21610859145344));
#795=CARTESIAN_POINT('',(-6.47700000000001,-1.7931232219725,2.34494338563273));
#796=CARTESIAN_POINT('',(-6.47700000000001,-0.394858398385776,2.60217341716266));
#797=CARTESIAN_POINT('',(-6.47700000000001,0.30431037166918,2.73056865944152));
#798=CARTESIAN_POINT('',(-6.47700000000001,1.7027014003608,2.98706215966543));
#799=CARTESIAN_POINT('',(-6.47700000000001,2.40192365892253,3.11516041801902));
#800=CARTESIAN_POINT('',(-6.47700000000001,3.10116007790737,3.24318091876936));
#801=B_SPLINE_CURVE_WITH_KNOTS('',3,(#781,#782,#783,#784,#785,#786,#787,#788,#789,#790,#791,
#792,#793,#794,#795,#796,#797,#798,#799,#800),.UNSPECIFIED.,.F.,.F.,(4,2,2,2,2,2,2,2,2,4),(0.,
0.789694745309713,1.57938589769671,2.26545823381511,3.39817786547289,4.53089908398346,
6.66350237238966,8.7961070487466,10.9286877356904,13.0612654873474),.UNSPECIFIED.);
#802=EDGE_CURVE('E349',#744,#778,#801,.T.);
#803=ORIENTED_EDGE('',*,*,#802,.F.);
#804=ORIENTED_EDGE('',*,*,#747,.F.);
#805=EDGE_LOOP('',(#776,#780,#803,#804));
#806=FACE_BOUND('',#805,.T.);
#807=ADVANCED_FACE('F363',(#806),#48,.T.);
#808=DIRECTION('',(0.,-1.,0.));
#809=VECTOR('',#808,1.);
#810=CARTESIAN_POINT('',(-6.47700000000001,-3.175,1.73669888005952));
#811=LINE('',#810,#809);
#812=CARTESIAN_POINT('',(-6.47700000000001,-4.826,1.73669888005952));
#813=VERTEX_POINT('',#812);
#814=EDGE_CURVE('E347',#778,#813,#811,.F.);
#815=ORIENTED_EDGE('',*,*,#814,.F.);
#816=ORIENTED_EDGE('',*,*,#779,.F.);
#817=DIRECTION('',(0.,-1.,0.));
#818=VECTOR('',#817,1.);
#819=CARTESIAN_POINT('',(-6.47700000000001,-3.175,-1.73669888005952));
#820=LINE('',#819,#818);
#821=CARTESIAN_POINT('',(-6.47700000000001,-4.826,-1.73669888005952));
#822=VERTEX_POINT('',#821);
#823=EDGE_CURVE('E341',#822,#774,#820,.T.);
#824=ORIENTED_EDGE('',*,*,#823,.F.);
#825=EDGE_CURVE('E340',#822,#813,#136,.T.);
#826=ORIENTED_EDGE('',*,*,#825,.T.);
#827=EDGE_LOOP('',(#815,#816,#824,#826));
#828=FACE_BOUND('',#827,.T.);
#829=ADVANCED_FACE('F368',(#828),#114,.T.);
#830=DIRECTION('',(0.,0.,-1.));
#831=VECTOR('',#830,1.);
#832=CARTESIAN_POINT('',(-6.47700000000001,-4.826,0.));
#833=LINE('',#832,#831);
#834=CARTESIAN_POINT('',(-6.47700000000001,-4.826,1.47560665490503));
#835=VERTEX_POINT('',#834);
#836=EDGE_CURVE('E343',#813,#835,#833,.T.);
#837=ORIENTED_EDGE('',*,*,#836,.F.);
#838=ORIENTED_EDGE('',*,*,#825,.F.);
#839=CARTESIAN_POINT('',(-6.47700000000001,-4.826,-1.47560665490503));
#840=VERTEX_POINT('',#839);
#841=EDGE_CURVE('E319',#840,#822,#833,.T.);
#842=ORIENTED_EDGE('',*,*,#841,.F.);
#843=EDGE_CURVE('E325',#840,#835,#164,.T.);
#844=ORIENTED_EDGE('',*,*,#843,.T.);
#845=EDGE_LOOP('',(#837,#838,#842,#844));
#846=FACE_BOUND('',#845,.T.);
#847=ADVANCED_FACE('F337',(#846),#146,.T.);
#848=CARTESIAN_POINT('',(-6.858,-3.175,0.));
#849=DIRECTION('',(0.,-1.,0.));
#850=DIRECTION('',(0.,0.,-1.));
#851=AXIS2_PLACEMENT_3D('',#848,#849,#850);
#852=CYLINDRICAL_SURFACE('',#851,1.524);
#853=DIRECTION('',(0.,-1.,0.));
#854=VECTOR('',#853,1.);
#855=CARTESIAN_POINT('',(-7.239,-3.175,1.47560665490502));
#856=LINE('',#855,#854);
#857=CARTESIAN_POINT('',(-7.239,-3.81,1.47560665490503));
#858=VERTEX_POINT('',#857);
#859=EDGE_CURVE('E11',#858,#157,#856,.T.);
#860=ORIENTED_EDGE('',*,*,#859,.F.);
#861=CARTESIAN_POINT('',(-6.47700000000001,-3.81,1.47560665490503));
#862=CARTESIAN_POINT('',(-6.47698025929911,-3.78892200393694,1.47558869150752));
#863=CARTESIAN_POINT('',(-6.47874778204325,-3.76785720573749,1.47605782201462));
#864=CARTESIAN_POINT('',(-6.48570229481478,-3.72637820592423,1.47783396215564));
#865=CARTESIAN_POINT('',(-6.49088233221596,-3.70596276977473,1.47913926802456));
#866=CARTESIAN_POINT('',(-6.50450730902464,-3.66631821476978,1.48245231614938));
#867=CARTESIAN_POINT('',(-6.512951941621,-3.64708898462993,1.48445999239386));
#868=CARTESIAN_POINT('',(-6.53284917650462,-3.61031280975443,1.48894503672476));
#869=CARTESIAN_POINT('',(-6.54430258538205,-3.59276631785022,1.49142253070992));
#870=CARTESIAN_POINT('',(-6.5701602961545,-3.55947598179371,1.4966298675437));
#871=CARTESIAN_POINT('',(-6.58461826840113,-3.54377444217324,1.49936371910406));
#872=CARTESIAN_POINT('',(-6.61595995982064,-3.51499085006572,1.50474087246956));
#873=CARTESIAN_POINT('',(-6.63284406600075,-3.50190921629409,1.50738415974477));
#874=CARTESIAN_POINT('',(-6.66884991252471,-3.47856392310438,1.51232684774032));
#875=CARTESIAN_POINT('',(-6.68799957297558,-3.46834210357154,1.51462093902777));
#876=CARTESIAN_POINT('',(-6.72781131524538,-3.4512790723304,1.51856064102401));
#877=CARTESIAN_POINT('',(-6.74847309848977,-3.44443719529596,1.52020637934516));
#878=CARTESIAN_POINT('',(-6.79027949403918,-3.43446392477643,1.52263563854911));
#879=CARTESIAN_POINT('',(-6.81140586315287,-3.43126021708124,1.52343594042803));
#880=CARTESIAN_POINT('',(-6.85391081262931,-3.42842721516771,1.52414263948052));
#881=CARTESIAN_POINT('',(-6.87528936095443,-3.42879747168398,1.52404914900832));
#882=CARTESIAN_POINT('',(-6.91718929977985,-3.43305001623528,1.52299125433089));
#883=CARTESIAN_POINT('',(-6.9377191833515,-3.43685416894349,1.52204622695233));
#884=CARTESIAN_POINT('',(-6.97783924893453,-3.44774088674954,1.51941401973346));
#885=CARTESIAN_POINT('',(-6.99742938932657,-3.4548235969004,1.51772680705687));
#886=CARTESIAN_POINT('',(-7.0353201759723,-3.47212968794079,1.51377014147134));
#887=CARTESIAN_POINT('',(-7.05360754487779,-3.48238091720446,1.5114955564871));
#888=CARTESIAN_POINT('',(-7.08822939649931,-3.5057117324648,1.5066109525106));
#889=CARTESIAN_POINT('',(-7.10456358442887,-3.51879174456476,1.50400088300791));
#890=CARTESIAN_POINT('',(-7.13528013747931,-3.54782586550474,1.49864660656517));
#891=CARTESIAN_POINT('',(-7.14959800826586,-3.56384795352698,1.49590068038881));
#892=CARTESIAN_POINT('',(-7.17536140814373,-3.59809917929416,1.49064790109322));
#893=CARTESIAN_POINT('',(-7.18680615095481,-3.61632891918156,1.48814111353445));
#894=CARTESIAN_POINT('',(-7.2065405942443,-3.65460747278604,1.48364377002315));
#895=CARTESIAN_POINT('',(-7.21481298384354,-3.67466554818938,1.48165606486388));
#896=CARTESIAN_POINT('',(-7.22783759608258,-3.71593754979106,1.47845929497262));
#897=CARTESIAN_POINT('',(-7.23259508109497,-3.73714969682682,1.47724906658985));
#898=CARTESIAN_POINT('',(-7.23667766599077,-3.76712126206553,1.47620465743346));
#899=CARTESIAN_POINT('',(-7.23754869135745,-3.77567940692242,1.47598075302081));
#900=CARTESIAN_POINT('',(-7.23870920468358,-3.79282367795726,1.4756818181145));
#901=CARTESIAN_POINT('',(-7.23899963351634,-3.80140973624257,1.47560654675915));
#902=CARTESIAN_POINT('',(-7.23900000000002,-3.81000000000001,1.47560665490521));
#903=B_SPLINE_CURVE_WITH_KNOTS('',3,(#861,#862,#863,#864,#865,#866,#867,#868,#869,#870,#871,
#872,#873,#874,#875,#876,#877,#878,#879,#880,#881,#882,#883,#884,#885,#886,#887,#888,#889,#890,
#891,#892,#893,#894,#895,#896,#897,#898,#899,#900,#901,#902),.UNSPECIFIED.,.F.,.F.,(4,2,2,2,2,2,
2,2,2,2,2,2,2,2,2,2,2,2,2,2,4),(0.,0.0631345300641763,0.126140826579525,0.189141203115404,
0.252158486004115,0.316416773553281,0.380685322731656,0.445850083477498,0.511002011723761,
0.574834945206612,0.638659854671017,0.701068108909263,0.763479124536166,0.826455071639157,
0.889440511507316,0.954124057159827,1.01882528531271,1.08387471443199,1.1488265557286,
1.17462559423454,1.20038279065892),.UNSPECIFIED.);
#904=CARTESIAN_POINT('',(-6.47700000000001,-3.81,1.47560665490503));
#905=VERTEX_POINT('',#904);
#906=EDGE_CURVE('E42',#905,#858,#903,.T.);
#907=ORIENTED_EDGE('',*,*,#906,.F.);
#908=DIRECTION('',(0.,-1.,0.));
#909=VECTOR('',#908,1.);
#910=CARTESIAN_POINT('',(-6.47700000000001,-3.175,1.47560665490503));
#911=LINE('',#910,#909);
#912=EDGE_CURVE('E292',#835,#905,#911,.F.);
#913=ORIENTED_EDGE('',*,*,#912,.F.);
#914=ORIENTED_EDGE('',*,*,#843,.F.);
#915=DIRECTION('',(0.,-1.,0.));
#916=VECTOR('',#915,1.);
#917=CARTESIAN_POINT('',(-6.47700000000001,-3.175,-1.47560665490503));
#918=LINE('',#917,#916);
#919=CARTESIAN_POINT('',(-6.47700000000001,-3.81,-1.47560665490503));
#920=VERTEX_POINT('',#919);
#921=EDGE_CURVE('E262',#920,#840,#918,.T.);
#922=ORIENTED_EDGE('',*,*,#921,.F.);
#923=CARTESIAN_POINT('',(-7.239,-3.81,-1.47560665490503));
#924=CARTESIAN_POINT('',(-7.2390197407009,-3.78892200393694,-1.47558869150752));
#925=CARTESIAN_POINT('',(-7.23725221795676,-3.76785720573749,-1.47605782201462));
#926=CARTESIAN_POINT('',(-7.23029770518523,-3.72637820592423,-1.47783396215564));
#927=CARTESIAN_POINT('',(-7.22511766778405,-3.70596276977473,-1.47913926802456));
#928=CARTESIAN_POINT('',(-7.21149269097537,-3.66631821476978,-1.48245231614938));
#929=CARTESIAN_POINT('',(-7.20304805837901,-3.64708898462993,-1.48445999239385));
#930=CARTESIAN_POINT('',(-7.18315082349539,-3.61031280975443,-1.48894503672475));
#931=CARTESIAN_POINT('',(-7.17169741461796,-3.59276631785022,-1.49142253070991));
#932=CARTESIAN_POINT('',(-7.14583970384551,-3.55947598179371,-1.4966298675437));
#933=CARTESIAN_POINT('',(-7.13138173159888,-3.54377444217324,-1.49936371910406));
#934=CARTESIAN_POINT('',(-7.10004004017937,-3.51499085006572,-1.50474087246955));
#935=CARTESIAN_POINT('',(-7.08315593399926,-3.50190921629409,-1.50738415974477));
#936=CARTESIAN_POINT('',(-7.0471500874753,-3.47856392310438,-1.51232684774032));
#937=CARTESIAN_POINT('',(-7.02800042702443,-3.46834210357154,-1.51462093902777));
#938=CARTESIAN_POINT('',(-6.98818868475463,-3.4512790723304,-1.51856064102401));
#939=CARTESIAN_POINT('',(-6.96752690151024,-3.44443719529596,-1.52020637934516));
#940=CARTESIAN_POINT('',(-6.92572050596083,-3.43446392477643,-1.52263563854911));
#941=CARTESIAN_POINT('',(-6.90459413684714,-3.43126021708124,-1.52343594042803));
#942=CARTESIAN_POINT('',(-6.8620891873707,-3.42842721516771,-1.52414263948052));
#943=CARTESIAN_POINT('',(-6.84071063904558,-3.42879747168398,-1.52404914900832));
#944=CARTESIAN_POINT('',(-6.79881070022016,-3.43305001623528,-1.52299125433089));
#945=CARTESIAN_POINT('',(-6.77828081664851,-3.43685416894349,-1.52204622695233));
#946=CARTESIAN_POINT('',(-6.73816075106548,-3.44774088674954,-1.51941401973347));
#947=CARTESIAN_POINT('',(-6.71857061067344,-3.4548235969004,-1.51772680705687));
#948=CARTESIAN_POINT('',(-6.68067982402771,-3.47212968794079,-1.51377014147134));
#949=CARTESIAN_POINT('',(-6.66239245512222,-3.48238091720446,-1.5114955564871));
#950=CARTESIAN_POINT('',(-6.6277706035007,-3.5057117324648,-1.5066109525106));
#951=CARTESIAN_POINT('',(-6.61143641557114,-3.51879174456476,-1.50400088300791));
#952=CARTESIAN_POINT('',(-6.58071986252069,-3.54782586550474,-1.49864660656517));
#953=CARTESIAN_POINT('',(-6.56640199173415,-3.56384795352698,-1.49590068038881));
#954=CARTESIAN_POINT('',(-6.54063859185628,-3.59809917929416,-1.49064790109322));
#955=CARTESIAN_POINT('',(-6.5291938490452,-3.61632891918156,-1.48814111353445));
#956=CARTESIAN_POINT('',(-6.50945940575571,-3.65460747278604,-1.48364377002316));
#957=CARTESIAN_POINT('',(-6.50118701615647,-3.67466554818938,-1.48165606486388));
#958=CARTESIAN_POINT('',(-6.48816240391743,-3.71593754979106,-1.47845929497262));
#959=CARTESIAN_POINT('',(-6.48340491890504,-3.73714969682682,-1.47724906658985));
#960=CARTESIAN_POINT('',(-6.47932233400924,-3.76712126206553,-1.47620465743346));
#961=CARTESIAN_POINT('',(-6.47845130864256,-3.77567940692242,-1.47598075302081));
#962=CARTESIAN_POINT('',(-6.47729079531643,-3.79282367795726,-1.47568181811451));
#963=CARTESIAN_POINT('',(-6.47700036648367,-3.80140973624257,-1.47560654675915));
#964=CARTESIAN_POINT('',(-6.47699999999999,-3.81000000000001,-1.47560665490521));
#965=B_SPLINE_CURVE_WITH_KNOTS('',3,(#923,#924,#925,#926,#927,#928,#929,#930,#931,#932,#933,
#934,#935,#936,#937,#938,#939,#940,#941,#942,#943,#944,#945,#946,#947,#948,#949,#950,#951,#952,
#953,#954,#955,#956,#957,#958,#959,#960,#961,#962,#963,#964),.UNSPECIFIED.,.F.,.F.,(4,2,2,2,2,2,
2,2,2,2,2,2,2,2,2,2,2,2,2,2,4),(0.,0.0631345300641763,0.126140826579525,0.189141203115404,
0.252158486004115,0.316416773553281,0.380685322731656,0.445850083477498,0.511002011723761,
0.57483494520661,0.638659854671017,0.701068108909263,0.763479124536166,0.826455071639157,
0.889440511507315,0.954124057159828,1.01882528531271,1.08387471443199,1.14882655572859,
1.17462559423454,1.20038279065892),.UNSPECIFIED.);
#966=CARTESIAN_POINT('',(-7.239,-3.81,-1.47560665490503));
#967=VERTEX_POINT('',#966);
#968=EDGE_CURVE('E264',#967,#920,#965,.T.);
#969=ORIENTED_EDGE('',*,*,#968,.F.);
#970=DIRECTION('',(0.,-1.,0.));
#971=VECTOR('',#970,1.);
#972=CARTESIAN_POINT('',(-7.239,-3.175,-1.47560665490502));
#973=LINE('',#972,#971);
#974=EDGE_CURVE('E272',#152,#967,#973,.F.);
#975=ORIENTED_EDGE('',*,*,#974,.F.);
#976=ORIENTED_EDGE('',*,*,#165,.F.);
#977=EDGE_LOOP('',(#860,#907,#913,#914,#922,#969,#975,#976));
#978=FACE_BOUND('',#977,.T.);
#979=ORIENTED_EDGE('',*,*,#182,.T.);
#980=EDGE_LOOP('',(#979));
#981=FACE_BOUND('',#980,.T.);
#982=ADVANCED_FACE('F274',(#978,#981),#852,.T.);
#983=CARTESIAN_POINT('',(-7.239,-7.874,-3.81));
#984=DIRECTION('',(-1.,0.,0.));
#985=DIRECTION('',(0.,-1.,0.));
#986=AXIS2_PLACEMENT_3D('',#983,#984,#985);
#987=PLANE('',#986);
#988=ORIENTED_EDGE('',*,*,#72,.T.);
#989=ORIENTED_EDGE('',*,*,#121,.T.);
#990=ORIENTED_EDGE('',*,*,#153,.T.);
#991=ORIENTED_EDGE('',*,*,#974,.T.);
#992=DIRECTION('',(0.,0.,1.));
#993=VECTOR('',#992,1.);
#994=CARTESIAN_POINT('',(-7.239,-3.81,-3.81));
#995=LINE('',#994,#993);
#996=EDGE_CURVE('E305',#967,#858,#995,.T.);
#997=ORIENTED_EDGE('',*,*,#996,.T.);
#998=ORIENTED_EDGE('',*,*,#859,.T.);
#999=ORIENTED_EDGE('',*,*,#158,.T.);
#1000=ORIENTED_EDGE('',*,*,#130,.T.);
#1001=ORIENTED_EDGE('',*,*,#98,.T.);
#1002=ORIENTED_EDGE('',*,*,#32,.F.);
#1003=EDGE_LOOP('',(#988,#989,#990,#991,#997,#998,#999,#1000,#1001,#1002));
#1004=FACE_BOUND('',#1003,.T.);
#1005=ADVANCED_FACE('F283',(#1004),#987,.F.);
#1006=CARTESIAN_POINT('',(-6.858,-3.81,-3.81));
#1007=DIRECTION('',(0.,0.,1.));
#1008=DIRECTION('',(1.,0.,0.));
#1009=AXIS2_PLACEMENT_3D('',#1006,#1007,#1008);
#1010=CYLINDRICAL_SURFACE('',#1009,0.380999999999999);
#1011=ORIENTED_EDGE('',*,*,#968,.T.);
#1012=DIRECTION('',(0.,0.,1.));
#1013=VECTOR('',#1012,1.);
#1014=CARTESIAN_POINT('',(-6.47700000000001,-3.81,-3.81));
#1015=LINE('',#1014,#1013);
#1016=EDGE_CURVE('E49',#920,#905,#1015,.T.);
#1017=ORIENTED_EDGE('',*,*,#1016,.T.);
#1018=ORIENTED_EDGE('',*,*,#906,.T.);
#1019=ORIENTED_EDGE('',*,*,#996,.F.);
#1020=EDGE_LOOP('',(#1011,#1017,#1018,#1019));
#1021=FACE_BOUND('',#1020,.T.);
#1022=ADVANCED_FACE('F278',(#1021),#1010,.F.);
#1023=CARTESIAN_POINT('',(-6.477,-7.874,-3.81));
#1024=DIRECTION('',(1.,0.,0.));
#1025=DIRECTION('',(0.,1.,0.));
#1026=AXIS2_PLACEMENT_3D('',#1023,#1024,#1025);
#1027=PLANE('',#1026);
#1028=ORIENTED_EDGE('',*,*,#802,.T.);
#1029=ORIENTED_EDGE('',*,*,#814,.T.);
#1030=ORIENTED_EDGE('',*,*,#836,.T.);
#1031=ORIENTED_EDGE('',*,*,#912,.T.);
#1032=ORIENTED_EDGE('',*,*,#1016,.F.);
#1033=ORIENTED_EDGE('',*,*,#921,.T.);
#1034=ORIENTED_EDGE('',*,*,#841,.T.);
#1035=ORIENTED_EDGE('',*,*,#823,.T.);
#1036=ORIENTED_EDGE('',*,*,#775,.T.);
#1037=ORIENTED_EDGE('',*,*,#745,.T.);
#1038=EDGE_LOOP('',(#1028,#1029,#1030,#1031,#1032,#1033,#1034,#1035,#1036,#1037));
#1039=FACE_BOUND('',#1038,.T.);
#1040=ADVANCED_FACE('F282',(#1039),#1027,.F.);
#1041=CLOSED_SHELL('',(#43,#109,#141,#169,#220,#251,#284,#315,#348,#379,#412,#443,#474,#505,
#538,#569,#602,#633,#666,#688,#712,#736,#751,#807,#829,#847,#982,#1005,#1022,#1040));
#1042=MANIFOLD_SOLID_BREP('B2',#1041);
#1043=ADVANCED_BREP_SHAPE_REPRESENTATION('',(#18,#1042),#14);
#1044=SHAPE_DEFINITION_REPRESENTATION(#9,#1043);
ENDSEC;
END-ISO-10303-21;
